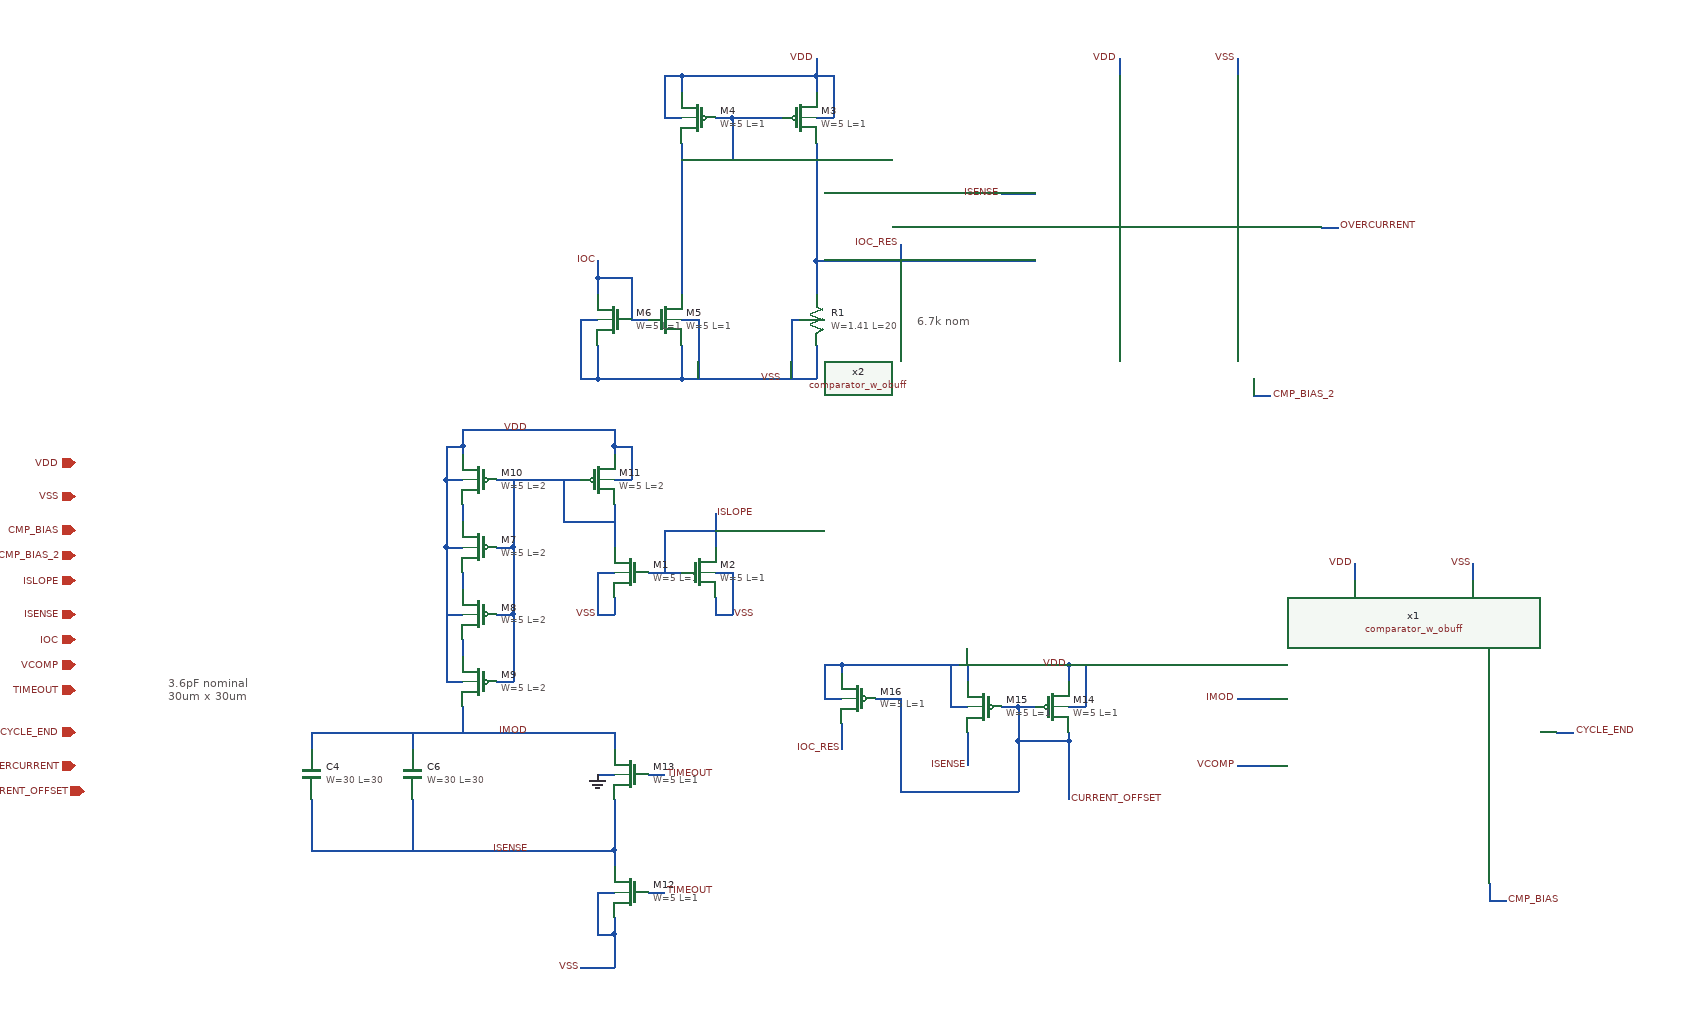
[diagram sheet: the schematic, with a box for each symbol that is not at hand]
v {xschem version=2.9.9 file_version=1.2 }
G {}
K {}
V {}
S {}
E {}
T {3.6pF nominal 
30um x 30um} -130 -530 0 0 0.4 0.4 {}
T {6.7k nom} 760 -960 0 0 0.4 0.4 {}
N 260 -760 360 -760 { lab=#net1}
N 200 -760 220 -760 { lab=VDD}
N 200 -800 200 -760 { lab=VDD}
N 200 -800 220 -800 { lab=VDD}
N 220 -800 220 -790 { lab=VDD}
N 400 -760 420 -760 { lab=VDD}
N 420 -800 420 -760 { lab=VDD}
N 400 -800 420 -800 { lab=VDD}
N 400 -800 400 -790 { lab=VDD}
N 400 -730 400 -690 { lab=#net1}
N 340 -760 340 -710 { lab=#net1}
N 350 -710 400 -710 { lab=#net1}
N 340 -710 350 -710 { lab=#net1}
N 380 -410 400 -410 { lab=GND}
N 440 -270 460 -270 { lab=TIMEOUT}
N 440 -410 460 -410 { lab=TIMEOUT}
N 40 -380 40 -320 { lab=ISENSE}
N 40 -320 400 -320 { lab=ISENSE}
N 400 -320 400 -300 { lab=ISENSE}
N 160 -380 160 -320 { lab=ISENSE}
N 40 -460 40 -440 { lab=IMOD}
N 40 -460 400 -460 { lab=IMOD}
N 400 -460 400 -440 { lab=IMOD}
N 160 -460 160 -440 { lab=IMOD}
N 400 -380 400 -320 { lab=ISENSE}
N 400 -240 400 -220 { lab=VSS}
N 380 -270 400 -270 { lab=VSS}
N 380 -270 380 -220 { lab=VSS}
N 380 -220 400 -220 { lab=VSS}
N 400 -220 400 -210 { lab=VSS}
N 1140 -500 1180 -500 { lab=IMOD}
N 1140 -420 1180 -420 { lab=VCOMP}
N 400 -210 400 -180 { lab=VSS}
N 360 -180 400 -180 { lab=VSS}
N 1280 -660 1280 -640 { lab=VDD}
N 1420 -660 1420 -640 { lab=VSS}
N 1440 -280 1440 -260 { lab=CMP_BIAS}
N 1440 -260 1460 -260 { lab=CMP_BIAS}
N 220 -820 220 -800 { lab=VDD}
N 220 -820 400 -820 { lab=VDD}
N 400 -820 400 -800 { lab=VDD}
N 1520 -460 1540 -460 { lab=CYCLE_END}
N 400 -690 400 -680 { lab=#net1}
N 380 -650 400 -650 { lab=VSS}
N 380 -650 380 -600 { lab=VSS}
N 380 -600 400 -600 { lab=VSS}
N 400 -620 400 -600 { lab=VSS}
N 520 -650 540 -650 { lab=VSS}
N 540 -650 540 -600 { lab=VSS}
N 520 -600 540 -600 { lab=VSS}
N 520 -620 520 -600 { lab=VSS}
N 440 -650 480 -650 { lab=ISLOPE}
N 520 -720 520 -680 { lab=ISLOPE}
N 460 -700 520 -700 { lab=ISLOPE}
N 460 -700 460 -650 { lab=ISLOPE}
N 860 -1100 900 -1100 { lab=ISENSE}
N 860 -1020 900 -1020 { lab=IOC_RES}
N 1000 -1260 1000 -1240 { lab=VDD}
N 1140 -1260 1140 -1240 { lab=VSS}
N 1160 -880 1160 -860 { lab=CMP_BIAS_2}
N 1160 -860 1180 -860 { lab=CMP_BIAS_2}
N 1240 -1060 1260 -1060 { lab=OVERCURRENT}
N 640 -920 640 -880 { lab=VSS}
N 600 -880 640 -880 { lab=VSS}
N 610 -950 620 -950 { lab=VSS}
N 610 -950 610 -880 { lab=VSS}
N 640 -1020 640 -980 { lab=IOC_RES}
N 760 -1020 860 -1020 { lab=IOC_RES}
N 640 -1160 640 -1020 { lab=IOC_RES}
N 640 -1020 760 -1020 { lab=IOC_RES}
N 640 -1190 660 -1190 { lab=VDD}
N 660 -1240 660 -1190 { lab=VDD}
N 640 -1240 660 -1240 { lab=VDD}
N 640 -1240 640 -1220 { lab=VDD}
N 640 -1260 640 -1240 { lab=VDD}
N 540 -1190 600 -1190 { lab=#net2}
N 520 -1190 540 -1190 { lab=#net2}
N 480 -1240 480 -1220 { lab=VDD}
N 480 -1240 640 -1240 { lab=VDD}
N 460 -1190 480 -1190 { lab=VDD}
N 460 -1240 460 -1190 { lab=VDD}
N 460 -1240 480 -1240 { lab=VDD}
N 480 -1160 480 -1100 { lab=#net2}
N 480 -920 480 -880 { lab=VSS}
N 480 -880 600 -880 { lab=VSS}
N 480 -950 500 -950 { lab=VSS}
N 500 -950 500 -880 { lab=VSS}
N 420 -950 440 -950 { lab=IOC}
N 480 -1100 480 -980 { lab=#net2}
N 380 -920 380 -880 { lab=VSS}
N 380 -880 480 -880 { lab=VSS}
N 380 -1000 380 -980 { lab=IOC}
N 380 -1000 420 -1000 { lab=IOC}
N 420 -1000 420 -950 { lab=IOC}
N 380 -1020 380 -1000 { lab=IOC}
N 360 -950 380 -950 { lab=VSS}
N 360 -950 360 -880 { lab=VSS}
N 360 -880 380 -880 { lab=VSS}
N 480 -1140 540 -1140 { lab=#net2}
N 540 -1190 540 -1140 { lab=#net2}
N 260 -680 280 -680 { lab=#net1}
N 280 -760 280 -680 { lab=#net1}
N 220 -730 220 -710 { lab=#net3}
N 200 -680 220 -680 { lab=VDD}
N 200 -760 200 -680 { lab=VDD}
N 280 -680 280 -600 { lab=#net1}
N 260 -600 280 -600 { lab=#net1}
N 280 -600 280 -520 { lab=#net1}
N 260 -520 280 -520 { lab=#net1}
N 220 -570 220 -550 { lab=#net4}
N 220 -650 220 -630 { lab=#net5}
N 200 -520 220 -520 { lab=VDD}
N 200 -680 200 -520 { lab=VDD}
N 200 -600 220 -600 { lab=VDD}
N 220 -490 220 -460 { lab=IMOD}
N 880 -490 900 -490 { lab=CURRENT_OFFSET}
N 880 -490 880 -450 { lab=CURRENT_OFFSET}
N 880 -450 940 -450 { lab=CURRENT_OFFSET}
N 940 -460 940 -450 { lab=CURRENT_OFFSET}
N 940 -540 940 -520 { lab=VDD}
N 860 -490 880 -490 { lab=CURRENT_OFFSET}
N 800 -490 820 -490 { lab=VDD}
N 800 -540 800 -490 { lab=VDD}
N 800 -540 940 -540 { lab=VDD}
N 940 -490 960 -490 { lab=VDD}
N 960 -540 960 -490 { lab=VDD}
N 940 -540 960 -540 { lab=VDD}
N 820 -540 820 -520 { lab=VDD}
N 940 -450 940 -380 { lab=CURRENT_OFFSET}
N 820 -460 820 -420 { lab=ISENSE}
N 670 -540 670 -530 { lab=VDD}
N 670 -540 810 -540 { lab=VDD}
N 650 -500 670 -500 { lab=VDD}
N 650 -540 650 -500 { lab=VDD}
N 650 -540 670 -540 { lab=VDD}
N 880 -450 880 -390 { lab=CURRENT_OFFSET}
N 740 -390 880 -390 { lab=CURRENT_OFFSET}
N 740 -500 740 -390 { lab=CURRENT_OFFSET}
N 710 -500 740 -500 { lab=CURRENT_OFFSET}
N 670 -470 670 -440 { lab=IOC_RES}
N 740 -1040 740 -1020 { lab=IOC_RES}
C {devices/ipin.sym} -240 -600 0 0 {name=p1 lab=ISENSE}
C {devices/ipin.sym} -240 -540 0 0 {name=p2 lab=VCOMP
}
C {devices/ipin.sym} -240 -510 0 0 {name=p3 lab=TIMEOUT}
C {devices/ipin.sym} -240 -780 0 0 {name=p4 lab=VDD}
C {devices/ipin.sym} -240 -740 0 0 {name=p5 lab=VSS
}
C {devices/ipin.sym} -240 -700 0 0 {name=p9 lab=CMP_BIAS}
C {design/comparator/comparator_w_obuff.sym} 1340 -460 0 0 {name=x1}
C {devices/ipin.sym} -240 -640 0 0 {name=p6 lab=ISLOPE}
C {devices/ipin.sym} -240 -460 0 0 {name=p7 lab=CYCLE_END}
C {sky130_fd_pr/pfet_g5v0d10v5.sym} 240 -760 0 1 {name=M10
L=2
W=5
nf=1
mult=1
ad="'int((nf+1)/2) * W/nf * 0.29'" 
pd="'2*int((nf+1)/2) * (W/nf + 0.29)'"
as="'int((nf+2)/2) * W/nf * 0.29'" 
ps="'2*int((nf+2)/2) * (W/nf + 0.29)'"
nrd="'0.29 / W'" nrs="'0.29 / W'"
sa=0 sb=0 sd=0
model=pfet_g5v0d10v5
spiceprefix=X
}
C {sky130_fd_pr/pfet_g5v0d10v5.sym} 380 -760 0 0 {name=M11
L=2
W=5
nf=1
mult=12
ad="'int((nf+1)/2) * W/nf * 0.29'" 
pd="'2*int((nf+1)/2) * (W/nf + 0.29)'"
as="'int((nf+2)/2) * W/nf * 0.29'" 
ps="'2*int((nf+2)/2) * (W/nf + 0.29)'"
nrd="'0.29 / W'" nrs="'0.29 / W'"
sa=0 sb=0 sd=0
model=pfet_g5v0d10v5
spiceprefix=X
}
C {devices/lab_pin.sym} 520 -720 2 0 {name=l74 sig_type=std_logic lab=ISLOPE
}
C {sky130_fd_pr/nfet_g5v0d10v5.sym} 420 -270 0 1 {name=M12
L=1
W=5
nf=1
mult=4
ad="'int((nf+1)/2) * W/nf * 0.29'" 
pd="'2*int((nf+1)/2) * (W/nf + 0.29)'"
as="'int((nf+2)/2) * W/nf * 0.29'" 
ps="'2*int((nf+2)/2) * (W/nf + 0.29)'"
nrd="'0.29 / W'" nrs="'0.29 / W'"
sa=0 sb=0 sd=0
model=nfet_g5v0d10v5
spiceprefix=X
}
C {sky130_fd_pr/nfet_g5v0d10v5.sym} 420 -410 0 1 {name=M13
L=1
W=5
nf=1
mult=2
ad="'int((nf+1)/2) * W/nf * 0.29'" 
pd="'2*int((nf+1)/2) * (W/nf + 0.29)'"
as="'int((nf+2)/2) * W/nf * 0.29'" 
ps="'2*int((nf+2)/2) * (W/nf + 0.29)'"
nrd="'0.29 / W'" nrs="'0.29 / W'"
sa=0 sb=0 sd=0
model=nfet_g5v0d10v5
spiceprefix=X
}
C {devices/gnd.sym} 380 -410 1 0 {name=l76 lab=GND}
C {sky130_fd_pr/cap_mim_m3_1.sym} 40 -410 0 0 {name=C4 model=cap_mim_m3_1 W=30 L=30 MF=1 spiceprefix=X}
C {sky130_fd_pr/cap_mim_m3_2.sym} 160 -410 0 0 {name=C6 model=cap_mim_m3_2 W=30 L=30 MF=1 spiceprefix=X}
C {devices/lab_wire.sym} 460 -410 0 1 {name=l34 sig_type=std_logic lab=TIMEOUT}
C {devices/lab_wire.sym} 300 -320 0 0 {name=l1 sig_type=std_logic lab=ISENSE}
C {devices/lab_wire.sym} 460 -270 0 1 {name=l2 sig_type=std_logic lab=TIMEOUT}
C {devices/lab_wire.sym} 300 -460 0 0 {name=l3 sig_type=std_logic lab=IMOD}
C {devices/lab_wire.sym} 1140 -500 0 0 {name=l4 sig_type=std_logic lab=IMOD}
C {devices/lab_wire.sym} 1140 -420 0 0 {name=l5 sig_type=std_logic lab=VCOMP}
C {devices/lab_wire.sym} 360 -180 0 0 {name=l6 sig_type=std_logic lab=VSS}
C {devices/lab_wire.sym} 1420 -660 0 0 {name=l7 sig_type=std_logic lab=VSS}
C {devices/lab_wire.sym} 1280 -660 0 0 {name=l8 sig_type=std_logic lab=VDD}
C {devices/lab_pin.sym} 1460 -260 2 0 {name=l9 sig_type=std_logic lab=CMP_BIAS
}
C {devices/lab_wire.sym} 300 -820 0 0 {name=l10 sig_type=std_logic lab=VDD}
C {devices/lab_wire.sym} 1540 -460 0 1 {name=l11 sig_type=std_logic lab=CYCLE_END}
C {sky130_fd_pr/nfet_g5v0d10v5.sym} 420 -650 0 1 {name=M1
L=1
W=5
nf=1
mult=1
ad="'int((nf+1)/2) * W/nf * 0.29'" 
pd="'2*int((nf+1)/2) * (W/nf + 0.29)'"
as="'int((nf+2)/2) * W/nf * 0.29'" 
ps="'2*int((nf+2)/2) * (W/nf + 0.29)'"
nrd="'0.29 / W'" nrs="'0.29 / W'"
sa=0 sb=0 sd=0
model=nfet_g5v0d10v5
spiceprefix=X
}
C {devices/lab_wire.sym} 380 -600 0 0 {name=l12 sig_type=std_logic lab=VSS}
C {sky130_fd_pr/nfet_g5v0d10v5.sym} 500 -650 0 0 {name=M2
L=1
W=5
nf=1
mult=4
ad="'int((nf+1)/2) * W/nf * 0.29'" 
pd="'2*int((nf+1)/2) * (W/nf + 0.29)'"
as="'int((nf+2)/2) * W/nf * 0.29'" 
ps="'2*int((nf+2)/2) * (W/nf + 0.29)'"
nrd="'0.29 / W'" nrs="'0.29 / W'"
sa=0 sb=0 sd=0
model=nfet_g5v0d10v5
spiceprefix=X
}
C {devices/lab_wire.sym} 540 -600 0 1 {name=l13 sig_type=std_logic lab=VSS}
C {design/comparator/comparator_w_obuff.sym} 1060 -1060 0 0 {name=x2}
C {devices/lab_wire.sym} 1140 -1260 0 0 {name=l16 sig_type=std_logic lab=VSS}
C {devices/lab_wire.sym} 1000 -1260 0 0 {name=l17 sig_type=std_logic lab=VDD}
C {devices/ipin.sym} -240 -670 0 0 {name=p8 lab=CMP_BIAS_2}
C {devices/lab_pin.sym} 1180 -860 2 0 {name=l14 sig_type=std_logic lab=CMP_BIAS_2
}
C {devices/lab_wire.sym} 1260 -1060 0 1 {name=l15 sig_type=std_logic lab=OVERCURRENT}
C {devices/ipin.sym} -240 -420 0 0 {name=p10 lab=OVERCURRENT}
C {devices/lab_wire.sym} 860 -1100 0 0 {name=l18 sig_type=std_logic lab=ISENSE}
C {sky130_fd_pr/res_high_po_1p41.sym} 640 -950 0 0 {name=R1
W=1.41
L=20
model=res_high_po_1p41
spiceprefix=X
mult=1}
C {devices/lab_wire.sym} 600 -880 0 0 {name=l19 sig_type=std_logic lab=VSS}
C {sky130_fd_pr/pfet_g5v0d10v5.sym} 620 -1190 0 0 {name=M3
L=1
W=5
nf=1
mult=4
ad="'int((nf+1)/2) * W/nf * 0.29'" 
pd="'2*int((nf+1)/2) * (W/nf + 0.29)'"
as="'int((nf+2)/2) * W/nf * 0.29'" 
ps="'2*int((nf+2)/2) * (W/nf + 0.29)'"
nrd="'0.29 / W'" nrs="'0.29 / W'"
sa=0 sb=0 sd=0
model=pfet_g5v0d10v5
spiceprefix=X
}
C {devices/lab_wire.sym} 640 -1260 0 0 {name=l20 sig_type=std_logic lab=VDD}
C {sky130_fd_pr/pfet_g5v0d10v5.sym} 500 -1190 0 1 {name=M4
L=1
W=5
nf=1
mult=2
ad="'int((nf+1)/2) * W/nf * 0.29'" 
pd="'2*int((nf+1)/2) * (W/nf + 0.29)'"
as="'int((nf+2)/2) * W/nf * 0.29'" 
ps="'2*int((nf+2)/2) * (W/nf + 0.29)'"
nrd="'0.29 / W'" nrs="'0.29 / W'"
sa=0 sb=0 sd=0
model=pfet_g5v0d10v5
spiceprefix=X
}
C {devices/ipin.sym} -240 -570 0 0 {name=p11 lab=IOC}
C {devices/lab_pin.sym} 380 -1020 2 1 {name=l21 sig_type=std_logic lab=IOC
}
C {sky130_fd_pr/nfet_g5v0d10v5.sym} 460 -950 0 0 {name=M5
L=1
W=5
nf=1
mult=2
ad="'int((nf+1)/2) * W/nf * 0.29'" 
pd="'2*int((nf+1)/2) * (W/nf + 0.29)'"
as="'int((nf+2)/2) * W/nf * 0.29'" 
ps="'2*int((nf+2)/2) * (W/nf + 0.29)'"
nrd="'0.29 / W'" nrs="'0.29 / W'"
sa=0 sb=0 sd=0
model=nfet_g5v0d10v5
spiceprefix=X
}
C {sky130_fd_pr/nfet_g5v0d10v5.sym} 400 -950 0 1 {name=M6
L=1
W=5
nf=1
mult=4
ad="'int((nf+1)/2) * W/nf * 0.29'" 
pd="'2*int((nf+1)/2) * (W/nf + 0.29)'"
as="'int((nf+2)/2) * W/nf * 0.29'" 
ps="'2*int((nf+2)/2) * (W/nf + 0.29)'"
nrd="'0.29 / W'" nrs="'0.29 / W'"
sa=0 sb=0 sd=0
model=nfet_g5v0d10v5
spiceprefix=X
}
C {sky130_fd_pr/pfet_g5v0d10v5.sym} 240 -680 0 1 {name=M7
L=2
W=5
nf=1
mult=1
ad="'int((nf+1)/2) * W/nf * 0.29'" 
pd="'2*int((nf+1)/2) * (W/nf + 0.29)'"
as="'int((nf+2)/2) * W/nf * 0.29'" 
ps="'2*int((nf+2)/2) * (W/nf + 0.29)'"
nrd="'0.29 / W'" nrs="'0.29 / W'"
sa=0 sb=0 sd=0
model=pfet_g5v0d10v5
spiceprefix=X
}
C {sky130_fd_pr/pfet_g5v0d10v5.sym} 240 -600 0 1 {name=M8
L=2
W=5
nf=1
mult=1
ad="'int((nf+1)/2) * W/nf * 0.29'" 
pd="'2*int((nf+1)/2) * (W/nf + 0.29)'"
as="'int((nf+2)/2) * W/nf * 0.29'" 
ps="'2*int((nf+2)/2) * (W/nf + 0.29)'"
nrd="'0.29 / W'" nrs="'0.29 / W'"
sa=0 sb=0 sd=0
model=pfet_g5v0d10v5
spiceprefix=X
}
C {sky130_fd_pr/pfet_g5v0d10v5.sym} 240 -520 0 1 {name=M9
L=2
W=5
nf=1
mult=1
ad="'int((nf+1)/2) * W/nf * 0.29'" 
pd="'2*int((nf+1)/2) * (W/nf + 0.29)'"
as="'int((nf+2)/2) * W/nf * 0.29'" 
ps="'2*int((nf+2)/2) * (W/nf + 0.29)'"
nrd="'0.29 / W'" nrs="'0.29 / W'"
sa=0 sb=0 sd=0
model=pfet_g5v0d10v5
spiceprefix=X
}
C {devices/ipin.sym} -230 -390 0 0 {name=p12 lab=CURRENT_OFFSET}
C {sky130_fd_pr/pfet_g5v0d10v5.sym} 920 -490 0 0 {name=M14
L=1
W=5
nf=1
mult=2
ad="'int((nf+1)/2) * W/nf * 0.29'" 
pd="'2*int((nf+1)/2) * (W/nf + 0.29)'"
as="'int((nf+2)/2) * W/nf * 0.29'" 
ps="'2*int((nf+2)/2) * (W/nf + 0.29)'"
nrd="'0.29 / W'" nrs="'0.29 / W'"
sa=0 sb=0 sd=0
model=pfet_g5v0d10v5
spiceprefix=X
}
C {devices/lab_wire.sym} 940 -540 0 0 {name=l22 sig_type=std_logic lab=VDD}
C {sky130_fd_pr/pfet_g5v0d10v5.sym} 840 -490 0 1 {name=M15
L=1
W=5
nf=1
mult=16
ad="'int((nf+1)/2) * W/nf * 0.29'" 
pd="'2*int((nf+1)/2) * (W/nf + 0.29)'"
as="'int((nf+2)/2) * W/nf * 0.29'" 
ps="'2*int((nf+2)/2) * (W/nf + 0.29)'"
nrd="'0.29 / W'" nrs="'0.29 / W'"
sa=0 sb=0 sd=0
model=pfet_g5v0d10v5
spiceprefix=X
}
C {devices/lab_wire.sym} 940 -380 0 1 {name=l23 sig_type=std_logic lab=CURRENT_OFFSET}
C {devices/lab_wire.sym} 820 -420 0 0 {name=l24 sig_type=std_logic lab=ISENSE}
C {sky130_fd_pr/pfet_g5v0d10v5.sym} 690 -500 0 1 {name=M16
L=1
W=5
nf=1
mult=8
ad="'int((nf+1)/2) * W/nf * 0.29'" 
pd="'2*int((nf+1)/2) * (W/nf + 0.29)'"
as="'int((nf+2)/2) * W/nf * 0.29'" 
ps="'2*int((nf+2)/2) * (W/nf + 0.29)'"
nrd="'0.29 / W'" nrs="'0.29 / W'"
sa=0 sb=0 sd=0
model=pfet_g5v0d10v5
spiceprefix=X
}
C {devices/lab_pin.sym} 740 -1040 2 1 {name=l25 sig_type=std_logic lab=IOC_RES
}
C {devices/lab_pin.sym} 670 -440 2 1 {name=l26 sig_type=std_logic lab=IOC_RES
}
